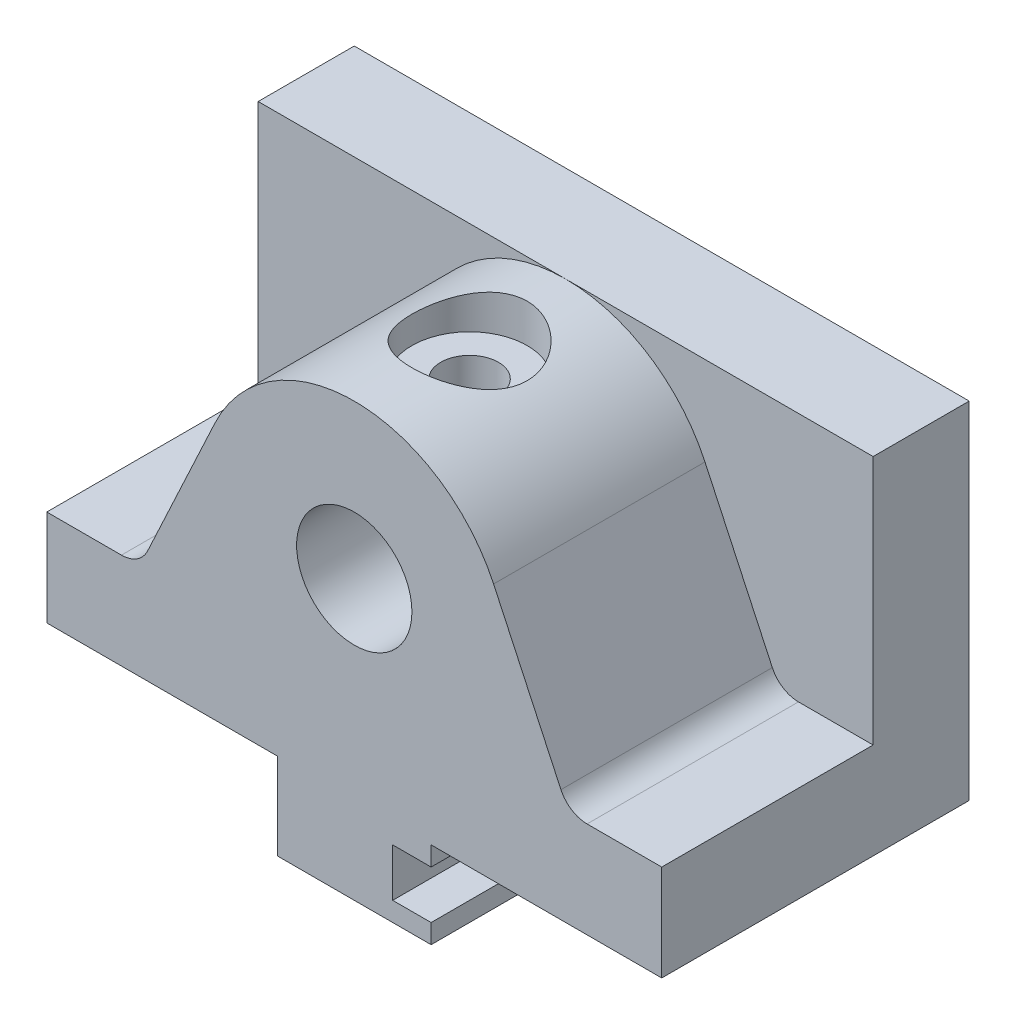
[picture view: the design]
ISO-10303-21;
HEADER;
FILE_DESCRIPTION(('STEP AP214'),'2;1');
FILE_NAME('part.step','',(''),(''),'','','');
FILE_SCHEMA(('AUTOMOTIVE_DESIGN { 1 0 10303 214 1 1 1 1 }'));
ENDSEC;
DATA;
#1=APPLICATION_CONTEXT('core data for automotive mechanical design processes');
#2=APPLICATION_PROTOCOL_DEFINITION('international standard','automotive_design',2000,#1);
#3=PRODUCT_CONTEXT('',#1,'mechanical');
#4=PRODUCT('Part','Part','',(#3));
#5=PRODUCT_RELATED_PRODUCT_CATEGORY('part','',(#4));
#6=PRODUCT_DEFINITION_FORMATION('','',#4);
#7=PRODUCT_DEFINITION_CONTEXT('part definition',#1,'design');
#8=PRODUCT_DEFINITION('design','',#6,#7);
#9=PRODUCT_DEFINITION_SHAPE('','',#8);
#10=(LENGTH_UNIT() NAMED_UNIT(*) SI_UNIT(.MILLI.,.METRE.));
#11=(NAMED_UNIT(*) PLANE_ANGLE_UNIT() SI_UNIT($,.RADIAN.));
#12=(NAMED_UNIT(*) SI_UNIT($,.STERADIAN.) SOLID_ANGLE_UNIT());
#13=UNCERTAINTY_MEASURE_WITH_UNIT(LENGTH_MEASURE(1.E-05),#10,'distance_accuracy_value','');
#14=(GEOMETRIC_REPRESENTATION_CONTEXT(3) GLOBAL_UNCERTAINTY_ASSIGNED_CONTEXT((#13)) GLOBAL_UNIT_ASSIGNED_CONTEXT((#10,
#11,#12)) REPRESENTATION_CONTEXT('',''));
#15=CARTESIAN_POINT('',(0.,0.,0.));
#16=DIRECTION('',(0.,0.,1.));
#17=DIRECTION('',(1.,0.,0.));
#18=AXIS2_PLACEMENT_3D('',#15,#16,#17);
#19=CARTESIAN_POINT('',(7.99999999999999,-9.,22.));
#20=DIRECTION('',(-1.,0.,0.));
#21=DIRECTION('',(0.,-1.,0.));
#22=AXIS2_PLACEMENT_3D('',#19,#20,#21);
#23=PLANE('',#22);
#24=DIRECTION('',(0.,1.,0.));
#25=VECTOR('',#24,1.);
#26=CARTESIAN_POINT('',(7.99999999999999,-9.,22.));
#27=LINE('',#26,#25);
#28=CARTESIAN_POINT('',(7.99999999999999,-2.,22.));
#29=VERTEX_POINT('',#28);
#30=CARTESIAN_POINT('',(8.,0.,22.));
#31=VERTEX_POINT('',#30);
#32=EDGE_CURVE('E333',#29,#31,#27,.T.);
#33=ORIENTED_EDGE('',*,*,#32,.F.);
#34=DIRECTION('',(0.,0.,1.));
#35=VECTOR('',#34,1.);
#36=CARTESIAN_POINT('',(7.99999999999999,-2.,-10.));
#37=LINE('',#36,#35);
#38=CARTESIAN_POINT('',(7.99999999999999,-2.,-10.));
#39=VERTEX_POINT('',#38);
#40=EDGE_CURVE('E218',#39,#29,#37,.T.);
#41=ORIENTED_EDGE('',*,*,#40,.F.);
#42=DIRECTION('',(0.,-1.,0.));
#43=VECTOR('',#42,1.);
#44=CARTESIAN_POINT('',(7.99999999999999,-9.,-10.));
#45=LINE('',#44,#43);
#46=CARTESIAN_POINT('',(8.,0.,-10.));
#47=VERTEX_POINT('',#46);
#48=EDGE_CURVE('E292',#47,#39,#45,.T.);
#49=ORIENTED_EDGE('',*,*,#48,.F.);
#50=DIRECTION('',(0.,0.,-1.));
#51=VECTOR('',#50,1.);
#52=CARTESIAN_POINT('',(8.,0.,22.));
#53=LINE('',#52,#51);
#54=EDGE_CURVE('E440',#31,#47,#53,.T.);
#55=ORIENTED_EDGE('',*,*,#54,.F.);
#56=EDGE_LOOP('',(#33,#41,#49,#55));
#57=FACE_BOUND('',#56,.T.);
#58=ADVANCED_FACE('F36',(#57),#23,.F.);
#59=CARTESIAN_POINT('',(-8.,0.,22.));
#60=DIRECTION('',(1.,0.,0.));
#61=DIRECTION('',(0.,1.,0.));
#62=AXIS2_PLACEMENT_3D('',#59,#60,#61);
#63=PLANE('',#62);
#64=DIRECTION('',(0.,0.,-1.));
#65=VECTOR('',#64,1.);
#66=CARTESIAN_POINT('',(-8.,0.,22.));
#67=LINE('',#66,#65);
#68=CARTESIAN_POINT('',(-8.,0.,22.));
#69=VERTEX_POINT('',#68);
#70=CARTESIAN_POINT('',(-8.,0.,-10.));
#71=VERTEX_POINT('',#70);
#72=EDGE_CURVE('E355',#69,#71,#67,.T.);
#73=ORIENTED_EDGE('',*,*,#72,.T.);
#74=DIRECTION('',(0.,1.,0.));
#75=VECTOR('',#74,1.);
#76=CARTESIAN_POINT('',(-8.,0.,-10.));
#77=LINE('',#76,#75);
#78=CARTESIAN_POINT('',(-8.00000000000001,-9.,-10.));
#79=VERTEX_POINT('',#78);
#80=EDGE_CURVE('E302',#79,#71,#77,.T.);
#81=ORIENTED_EDGE('',*,*,#80,.F.);
#82=DIRECTION('',(0.,0.,-1.));
#83=VECTOR('',#82,1.);
#84=CARTESIAN_POINT('',(-8.00000000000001,-9.,22.));
#85=LINE('',#84,#83);
#86=CARTESIAN_POINT('',(-8.00000000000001,-9.,22.));
#87=VERTEX_POINT('',#86);
#88=EDGE_CURVE('E378',#87,#79,#85,.T.);
#89=ORIENTED_EDGE('',*,*,#88,.F.);
#90=DIRECTION('',(0.,-1.,0.));
#91=VECTOR('',#90,1.);
#92=CARTESIAN_POINT('',(-8.,0.,22.));
#93=LINE('',#92,#91);
#94=EDGE_CURVE('E327',#69,#87,#93,.T.);
#95=ORIENTED_EDGE('',*,*,#94,.F.);
#96=EDGE_LOOP('',(#73,#81,#89,#95));
#97=FACE_BOUND('',#96,.T.);
#98=ADVANCED_FACE('F261',(#97),#63,.F.);
#99=CARTESIAN_POINT('',(-8.00000000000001,-9.,22.));
#100=DIRECTION('',(0.,1.,0.));
#101=DIRECTION('',(0.,0.,1.));
#102=AXIS2_PLACEMENT_3D('',#99,#100,#101);
#103=PLANE('',#102);
#104=CARTESIAN_POINT('',(0.,-9.,14.));
#105=DIRECTION('',(0.,-1.,0.));
#106=DIRECTION('',(0.,0.,-1.));
#107=AXIS2_PLACEMENT_3D('',#104,#105,#106);
#108=CIRCLE('',#107,3.);
#109=CARTESIAN_POINT('',(0.,-9.,11.));
#110=VERTEX_POINT('',#109);
#111=EDGE_CURVE('E233',#110,#110,#108,.T.);
#112=ORIENTED_EDGE('',*,*,#111,.F.);
#113=EDGE_LOOP('',(#112));
#114=FACE_BOUND('',#113,.T.);
#115=CARTESIAN_POINT('',(0.,-9.,-2.));
#116=DIRECTION('',(0.,-1.,0.));
#117=DIRECTION('',(0.,0.,-1.));
#118=AXIS2_PLACEMENT_3D('',#115,#116,#117);
#119=CIRCLE('',#118,3.);
#120=CARTESIAN_POINT('',(0.,-9.,-5.));
#121=VERTEX_POINT('',#120);
#122=EDGE_CURVE('E540',#121,#121,#119,.T.);
#123=ORIENTED_EDGE('',*,*,#122,.F.);
#124=EDGE_LOOP('',(#123));
#125=FACE_BOUND('',#124,.T.);
#126=ORIENTED_EDGE('',*,*,#88,.T.);
#127=DIRECTION('',(-1.,0.,0.));
#128=VECTOR('',#127,1.);
#129=CARTESIAN_POINT('',(-8.00000000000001,-9.,-10.));
#130=LINE('',#129,#128);
#131=CARTESIAN_POINT('',(7.99999999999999,-9.,-10.));
#132=VERTEX_POINT('',#131);
#133=EDGE_CURVE('E295',#132,#79,#130,.T.);
#134=ORIENTED_EDGE('',*,*,#133,.F.);
#135=DIRECTION('',(0.,0.,-1.));
#136=VECTOR('',#135,1.);
#137=CARTESIAN_POINT('',(7.99999999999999,-9.,22.));
#138=LINE('',#137,#136);
#139=CARTESIAN_POINT('',(7.99999999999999,-9.,22.));
#140=VERTEX_POINT('',#139);
#141=EDGE_CURVE('E289',#140,#132,#138,.T.);
#142=ORIENTED_EDGE('',*,*,#141,.F.);
#143=DIRECTION('',(1.,0.,0.));
#144=VECTOR('',#143,1.);
#145=CARTESIAN_POINT('',(-8.00000000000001,-9.,22.));
#146=LINE('',#145,#144);
#147=EDGE_CURVE('E330',#87,#140,#146,.T.);
#148=ORIENTED_EDGE('',*,*,#147,.F.);
#149=EDGE_LOOP('',(#126,#134,#142,#148));
#150=FACE_BOUND('',#149,.T.);
#151=ADVANCED_FACE('F268',(#114,#125,#150),#103,.F.);
#152=CARTESIAN_POINT('',(7.99999999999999,-7.,-10.));
#153=VERTEX_POINT('',#152);
#154=EDGE_CURVE('E285',#153,#132,#45,.T.);
#155=ORIENTED_EDGE('',*,*,#154,.F.);
#156=DIRECTION('',(0.,0.,1.));
#157=VECTOR('',#156,1.);
#158=CARTESIAN_POINT('',(7.99999999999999,-7.,-10.));
#159=LINE('',#158,#157);
#160=CARTESIAN_POINT('',(7.99999999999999,-7.,22.));
#161=VERTEX_POINT('',#160);
#162=EDGE_CURVE('E55',#153,#161,#159,.T.);
#163=ORIENTED_EDGE('',*,*,#162,.T.);
#164=EDGE_CURVE('E334',#140,#161,#27,.T.);
#165=ORIENTED_EDGE('',*,*,#164,.F.);
#166=ORIENTED_EDGE('',*,*,#141,.T.);
#167=EDGE_LOOP('',(#155,#163,#165,#166));
#168=FACE_BOUND('',#167,.T.);
#169=ADVANCED_FACE('F264',(#168),#23,.F.);
#170=CARTESIAN_POINT('',(8.,0.,22.));
#171=DIRECTION('',(0.,1.,0.));
#172=DIRECTION('',(0.,0.,1.));
#173=AXIS2_PLACEMENT_3D('',#170,#171,#172);
#174=PLANE('',#173);
#175=ORIENTED_EDGE('',*,*,#54,.T.);
#176=DIRECTION('',(-1.,0.,0.));
#177=VECTOR('',#176,1.);
#178=CARTESIAN_POINT('',(8.,0.,-10.));
#179=LINE('',#178,#177);
#180=CARTESIAN_POINT('',(32.,0.,-10.));
#181=VERTEX_POINT('',#180);
#182=EDGE_CURVE('E293',#181,#47,#179,.T.);
#183=ORIENTED_EDGE('',*,*,#182,.F.);
#184=DIRECTION('',(0.,0.,-1.));
#185=VECTOR('',#184,1.);
#186=CARTESIAN_POINT('',(32.,0.,22.));
#187=LINE('',#186,#185);
#188=CARTESIAN_POINT('',(32.,0.,22.));
#189=VERTEX_POINT('',#188);
#190=EDGE_CURVE('E422',#189,#181,#187,.T.);
#191=ORIENTED_EDGE('',*,*,#190,.F.);
#192=DIRECTION('',(1.,0.,0.));
#193=VECTOR('',#192,1.);
#194=CARTESIAN_POINT('',(8.,0.,22.));
#195=LINE('',#194,#193);
#196=EDGE_CURVE('E336',#31,#189,#195,.T.);
#197=ORIENTED_EDGE('',*,*,#196,.F.);
#198=EDGE_LOOP('',(#175,#183,#191,#197));
#199=FACE_BOUND('',#198,.T.);
#200=ADVANCED_FACE('F275',(#199),#174,.F.);
#201=CARTESIAN_POINT('',(32.,0.,22.));
#202=DIRECTION('',(-1.,0.,0.));
#203=DIRECTION('',(0.,0.,1.));
#204=AXIS2_PLACEMENT_3D('',#201,#202,#203);
#205=PLANE('',#204);
#206=ORIENTED_EDGE('',*,*,#190,.T.);
#207=DIRECTION('',(0.,-1.,0.));
#208=VECTOR('',#207,1.);
#209=CARTESIAN_POINT('',(32.,36.,-10.));
#210=LINE('',#209,#208);
#211=CARTESIAN_POINT('',(32.,36.,-10.));
#212=VERTEX_POINT('',#211);
#213=EDGE_CURVE('E312',#212,#181,#210,.T.);
#214=ORIENTED_EDGE('',*,*,#213,.F.);
#215=DIRECTION('',(0.,0.,1.));
#216=VECTOR('',#215,1.);
#217=CARTESIAN_POINT('',(32.,36.,-10.));
#218=LINE('',#217,#216);
#219=CARTESIAN_POINT('',(32.,36.,0.));
#220=VERTEX_POINT('',#219);
#221=EDGE_CURVE('E315',#212,#220,#218,.T.);
#222=ORIENTED_EDGE('',*,*,#221,.T.);
#223=DIRECTION('',(0.,-1.,0.));
#224=VECTOR('',#223,1.);
#225=CARTESIAN_POINT('',(32.,0.,0.));
#226=LINE('',#225,#224);
#227=CARTESIAN_POINT('',(32.,10.,0.));
#228=VERTEX_POINT('',#227);
#229=EDGE_CURVE('E297',#220,#228,#226,.T.);
#230=ORIENTED_EDGE('',*,*,#229,.T.);
#231=DIRECTION('',(0.,0.,-1.));
#232=VECTOR('',#231,1.);
#233=CARTESIAN_POINT('',(32.,10.,22.));
#234=LINE('',#233,#232);
#235=CARTESIAN_POINT('',(32.,10.,22.));
#236=VERTEX_POINT('',#235);
#237=EDGE_CURVE('E412',#236,#228,#234,.T.);
#238=ORIENTED_EDGE('',*,*,#237,.F.);
#239=DIRECTION('',(0.,1.,0.));
#240=VECTOR('',#239,1.);
#241=CARTESIAN_POINT('',(32.,0.,22.));
#242=LINE('',#241,#240);
#243=EDGE_CURVE('E338',#189,#236,#242,.T.);
#244=ORIENTED_EDGE('',*,*,#243,.F.);
#245=EDGE_LOOP('',(#206,#214,#222,#230,#238,#244));
#246=FACE_BOUND('',#245,.T.);
#247=ADVANCED_FACE('F281',(#246),#205,.F.);
#248=CARTESIAN_POINT('',(32.,10.,22.));
#249=DIRECTION('',(0.,-1.,0.));
#250=DIRECTION('',(1.,0.,0.));
#251=AXIS2_PLACEMENT_3D('',#248,#249,#250);
#252=PLANE('',#251);
#253=DIRECTION('',(-1.,0.,0.));
#254=VECTOR('',#253,1.);
#255=CARTESIAN_POINT('',(32.,10.,0.));
#256=LINE('',#255,#254);
#257=CARTESIAN_POINT('',(24.2283340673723,9.99999999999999,0.));
#258=VERTEX_POINT('',#257);
#259=EDGE_CURVE('E359',#228,#258,#256,.T.);
#260=ORIENTED_EDGE('',*,*,#259,.T.);
#261=DIRECTION('',(0.,0.,-1.));
#262=VECTOR('',#261,1.);
#263=CARTESIAN_POINT('',(24.2283340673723,9.99999999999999,22.));
#264=LINE('',#263,#262);
#265=CARTESIAN_POINT('',(24.2283340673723,9.99999999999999,22.));
#266=VERTEX_POINT('',#265);
#267=EDGE_CURVE('E63',#258,#266,#264,.F.);
#268=ORIENTED_EDGE('',*,*,#267,.T.);
#269=DIRECTION('',(-1.,0.,0.));
#270=VECTOR('',#269,1.);
#271=CARTESIAN_POINT('',(32.,10.,22.));
#272=LINE('',#271,#270);
#273=EDGE_CURVE('E340',#236,#266,#272,.T.);
#274=ORIENTED_EDGE('',*,*,#273,.F.);
#275=ORIENTED_EDGE('',*,*,#237,.T.);
#276=EDGE_LOOP('',(#260,#268,#274,#275));
#277=FACE_BOUND('',#276,.T.);
#278=ADVANCED_FACE('F410',(#277),#252,.F.);
#279=CARTESIAN_POINT('',(22.3171232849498,9.99999999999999,22.));
#280=DIRECTION('',(-0.906307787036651,-0.422618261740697,0.));
#281=DIRECTION('',(0.422618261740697,-0.906307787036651,0.));
#282=AXIS2_PLACEMENT_3D('',#279,#280,#281);
#283=PLANE('',#282);
#284=DIRECTION('',(-0.422618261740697,0.906307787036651,0.));
#285=VECTOR('',#284,1.);
#286=CARTESIAN_POINT('',(22.3171232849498,9.99999999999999,22.));
#287=LINE('',#286,#285);
#288=CARTESIAN_POINT('',(21.5094107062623,11.7321452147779,22.));
#289=VERTEX_POINT('',#288);
#290=CARTESIAN_POINT('',(14.5009245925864,26.7618921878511,22.));
#291=VERTEX_POINT('',#290);
#292=EDGE_CURVE('E342',#289,#291,#287,.T.);
#293=ORIENTED_EDGE('',*,*,#292,.F.);
#294=DIRECTION('',(0.,0.,-1.));
#295=VECTOR('',#294,1.);
#296=CARTESIAN_POINT('',(21.5094107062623,11.7321452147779,0.));
#297=LINE('',#296,#295);
#298=CARTESIAN_POINT('',(21.5094107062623,11.7321452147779,0.));
#299=VERTEX_POINT('',#298);
#300=EDGE_CURVE('E382',#289,#299,#297,.T.);
#301=ORIENTED_EDGE('',*,*,#300,.T.);
#302=DIRECTION('',(-0.422618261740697,0.906307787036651,0.));
#303=VECTOR('',#302,1.);
#304=CARTESIAN_POINT('',(22.3171232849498,9.99999999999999,0.));
#305=LINE('',#304,#303);
#306=CARTESIAN_POINT('',(14.5009245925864,26.7618921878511,0.));
#307=VERTEX_POINT('',#306);
#308=EDGE_CURVE('E356',#299,#307,#305,.T.);
#309=ORIENTED_EDGE('',*,*,#308,.T.);
#310=DIRECTION('',(0.,0.,-1.));
#311=VECTOR('',#310,1.);
#312=CARTESIAN_POINT('',(14.5009245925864,26.7618921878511,22.));
#313=LINE('',#312,#311);
#314=EDGE_CURVE('E402',#291,#307,#313,.T.);
#315=ORIENTED_EDGE('',*,*,#314,.F.);
#316=EDGE_LOOP('',(#293,#301,#309,#315));
#317=FACE_BOUND('',#316,.T.);
#318=ADVANCED_FACE('F399',(#317),#283,.F.);
#319=CARTESIAN_POINT('',(0.,20.,22.));
#320=DIRECTION('',(0.,0.,-1.));
#321=DIRECTION('',(-1.,0.,0.));
#322=AXIS2_PLACEMENT_3D('',#319,#320,#321);
#323=CYLINDRICAL_SURFACE('',#322,16.);
#324=CARTESIAN_POINT('',(0.,36.,16.));
#325=CARTESIAN_POINT('',(-0.162427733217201,36.0000005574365,16.0000007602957));
#326=CARTESIAN_POINT('',(-0.324844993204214,35.997521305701,15.9933993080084));
#327=CARTESIAN_POINT('',(-0.648520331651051,35.9876715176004,15.9670588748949));
#328=CARTESIAN_POINT('',(-0.809777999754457,35.9802993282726,15.9473154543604));
#329=CARTESIAN_POINT('',(-1.12979634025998,35.9608661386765,15.8948993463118));
#330=CARTESIAN_POINT('',(-1.28855831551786,35.9488076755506,15.862233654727));
#331=CARTESIAN_POINT('',(-1.60261141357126,35.920317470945,15.7842738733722));
#332=CARTESIAN_POINT('',(-1.75790116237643,35.9038840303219,15.7389748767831));
#333=CARTESIAN_POINT('',(-2.06353693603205,35.8671186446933,15.6362882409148));
#334=CARTESIAN_POINT('',(-2.2138937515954,35.8467959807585,15.5789293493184));
#335=CARTESIAN_POINT('',(-2.50915130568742,35.8027355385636,15.4525186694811));
#336=CARTESIAN_POINT('',(-2.6540499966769,35.7789964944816,15.3834625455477));
#337=CARTESIAN_POINT('',(-2.93745114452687,35.7287028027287,15.2342168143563));
#338=CARTESIAN_POINT('',(-3.07595454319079,35.7021485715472,15.1540288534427));
#339=CARTESIAN_POINT('',(-3.3458591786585,35.6468595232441,14.9830470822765));
#340=CARTESIAN_POINT('',(-3.47725782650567,35.618123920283,14.8922494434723));
#341=CARTESIAN_POINT('',(-3.73705610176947,35.5580480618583,14.6970003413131));
#342=CARTESIAN_POINT('',(-3.86515055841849,35.5266502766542,14.5921603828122));
#343=CARTESIAN_POINT('',(-4.11214204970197,35.4630706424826,14.372369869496));
#344=CARTESIAN_POINT('',(-4.23103881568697,35.4308887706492,14.2574190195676));
#345=CARTESIAN_POINT('',(-4.45900396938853,35.3665649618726,14.0180360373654));
#346=CARTESIAN_POINT('',(-4.56806779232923,35.334423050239,13.8935995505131));
#347=CARTESIAN_POINT('',(-4.7756151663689,35.2710599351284,13.6360477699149));
#348=CARTESIAN_POINT('',(-4.87410227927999,35.2398384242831,13.5029354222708));
#349=CARTESIAN_POINT('',(-5.06349317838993,35.1779887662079,13.2234482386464));
#350=CARTESIAN_POINT('',(-5.15395768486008,35.1474300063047,13.0767598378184));
#351=CARTESIAN_POINT('',(-5.32210766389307,35.0891712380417,12.7757656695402));
#352=CARTESIAN_POINT('',(-5.39979826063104,35.0614700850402,12.6214629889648));
#353=CARTESIAN_POINT('',(-5.54178841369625,35.0098065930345,12.3061815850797));
#354=CARTESIAN_POINT('',(-5.60608640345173,34.9858446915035,12.1452020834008));
#355=CARTESIAN_POINT('',(-5.72063465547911,34.9424928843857,11.81780057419));
#356=CARTESIAN_POINT('',(-5.77089169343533,34.9231007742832,11.6513812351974));
#357=CARTESIAN_POINT('',(-5.85511762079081,34.8902504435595,11.3211525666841));
#358=CARTESIAN_POINT('',(-5.88966490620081,34.8765832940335,11.1575115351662));
#359=CARTESIAN_POINT('',(-5.94499608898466,34.8545586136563,10.8276330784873));
#360=CARTESIAN_POINT('',(-5.96578600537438,34.8461987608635,10.6613968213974));
#361=CARTESIAN_POINT('',(-5.99338932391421,34.8350769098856,10.3276054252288));
#362=CARTESIAN_POINT('',(-6.00020481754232,34.8323140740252,10.1600504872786));
#363=CARTESIAN_POINT('',(-5.99978582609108,34.8324836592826,9.82496442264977));
#364=CARTESIAN_POINT('',(-5.99255188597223,34.8354158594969,9.65743329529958));
#365=CARTESIAN_POINT('',(-5.9649764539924,34.8465233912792,9.33379681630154));
#366=CARTESIAN_POINT('',(-5.94544909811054,34.8543729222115,9.17761005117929));
#367=CARTESIAN_POINT('',(-5.89424692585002,34.8747642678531,8.86749914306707));
#368=CARTESIAN_POINT('',(-5.86256807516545,34.887307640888,8.713575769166));
#369=CARTESIAN_POINT('',(-5.78737202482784,34.9167004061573,8.40911721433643));
#370=CARTESIAN_POINT('',(-5.74385788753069,34.9335486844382,8.25858116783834));
#371=CARTESIAN_POINT('',(-5.64535023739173,34.9710653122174,7.96174446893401));
#372=CARTESIAN_POINT('',(-5.59035233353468,34.9917351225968,7.8154454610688));
#373=CARTESIAN_POINT('',(-5.46820476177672,35.0367233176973,7.52533536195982));
#374=CARTESIAN_POINT('',(-5.40084887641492,35.0611021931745,7.3816205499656));
#375=CARTESIAN_POINT('',(-5.25517504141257,35.112547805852,7.10030421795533));
#376=CARTESIAN_POINT('',(-5.17685336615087,35.1396154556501,6.96270479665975));
#377=CARTESIAN_POINT('',(-5.00978390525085,35.1957174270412,6.69439199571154));
#378=CARTESIAN_POINT('',(-4.92103495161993,35.2247519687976,6.56367938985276));
#379=CARTESIAN_POINT('',(-4.73365945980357,35.2840480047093,6.30982948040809));
#380=CARTESIAN_POINT('',(-4.63503247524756,35.3143095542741,6.18669251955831));
#381=CARTESIAN_POINT('',(-4.42148606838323,35.3773753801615,5.94059609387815));
#382=CARTESIAN_POINT('',(-4.30591643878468,35.4102134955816,5.81820873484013));
#383=CARTESIAN_POINT('',(-4.06489568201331,35.4755357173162,5.58356444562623));
#384=CARTESIAN_POINT('',(-3.93944756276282,35.5080199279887,5.47130445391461));
#385=CARTESIAN_POINT('',(-3.67930542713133,35.5717902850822,5.25752502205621));
#386=CARTESIAN_POINT('',(-3.54460652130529,35.6030757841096,5.15601133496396));
#387=CARTESIAN_POINT('',(-3.26687700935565,35.6635788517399,4.96453057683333));
#388=CARTESIAN_POINT('',(-3.1238497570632,35.6927972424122,4.87455890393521));
#389=CARTESIAN_POINT('',(-2.8279450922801,35.7488334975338,4.7054533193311));
#390=CARTESIAN_POINT('',(-2.67494692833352,35.7756056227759,4.62651523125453));
#391=CARTESIAN_POINT('',(-2.3622882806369,35.8254428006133,4.48191640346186));
#392=CARTESIAN_POINT('',(-2.20263047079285,35.8485093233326,4.4162503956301));
#393=CARTESIAN_POINT('',(-1.87775996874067,35.8902747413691,4.29878554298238));
#394=CARTESIAN_POINT('',(-1.71254812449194,35.9089742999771,4.24698459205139));
#395=CARTESIAN_POINT('',(-1.37781252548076,35.941452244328,4.15777194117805));
#396=CARTESIAN_POINT('',(-1.20828902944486,35.9552309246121,4.12035938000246));
#397=CARTESIAN_POINT('',(-0.875397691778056,35.9768584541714,4.06192787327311));
#398=CARTESIAN_POINT('',(-0.71218192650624,35.9849836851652,4.04014291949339));
#399=CARTESIAN_POINT('',(-0.384342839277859,35.9962238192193,4.01006070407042));
#400=CARTESIAN_POINT('',(-0.219719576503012,35.9993389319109,4.00176287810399));
#401=CARTESIAN_POINT('',(0.10963649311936,36.0004717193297,3.99874206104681));
#402=CARTESIAN_POINT('',(0.274369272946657,35.9984903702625,4.0040164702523));
#403=CARTESIAN_POINT('',(0.602703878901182,35.9894877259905,4.02807883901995));
#404=CARTESIAN_POINT('',(0.766305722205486,35.9824665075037,4.04686659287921));
#405=CARTESIAN_POINT('',(1.08484961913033,35.9639458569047,4.09677376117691));
#406=CARTESIAN_POINT('',(1.23988188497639,35.9526301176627,4.1273881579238));
#407=CARTESIAN_POINT('',(1.54675761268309,35.9258052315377,4.20065226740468));
#408=CARTESIAN_POINT('',(1.69860000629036,35.9102947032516,4.24330594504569));
#409=CARTESIAN_POINT('',(1.99802063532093,35.8754724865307,4.3402587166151));
#410=CARTESIAN_POINT('',(2.14560001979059,35.85616183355,4.39455463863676));
#411=CARTESIAN_POINT('',(2.43569439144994,35.8141987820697,4.51437951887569));
#412=CARTESIAN_POINT('',(2.5782074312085,35.791545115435,4.57991274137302));
#413=CARTESIAN_POINT('',(2.8613459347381,35.7427421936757,4.72376640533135));
#414=CARTESIAN_POINT('',(3.00179672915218,35.7165106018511,4.80240263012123));
#415=CARTESIAN_POINT('',(3.27565209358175,35.6617244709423,4.97049434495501));
#416=CARTESIAN_POINT('',(3.40905422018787,35.6331691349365,5.05995355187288));
#417=CARTESIAN_POINT('',(3.66805220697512,35.574435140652,5.24909372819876));
#418=CARTESIAN_POINT('',(3.79364691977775,35.5442562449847,5.34877619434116));
#419=CARTESIAN_POINT('',(4.03634135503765,35.4830105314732,5.55774902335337));
#420=CARTESIAN_POINT('',(4.1534407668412,35.4519436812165,5.66703973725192));
#421=CARTESIAN_POINT('',(4.3850769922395,35.3878643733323,5.9012462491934));
#422=CARTESIAN_POINT('',(4.49906697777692,35.3548440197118,6.02670141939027));
#423=CARTESIAN_POINT('',(4.71608180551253,35.2895850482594,6.28687984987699));
#424=CARTESIAN_POINT('',(4.81911014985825,35.2573461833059,6.42160012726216));
#425=CARTESIAN_POINT('',(5.01360921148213,35.194544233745,6.69961873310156));
#426=CARTESIAN_POINT('',(5.10507411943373,35.163981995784,6.84292132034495));
#427=CARTESIAN_POINT('',(5.27567954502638,35.1054737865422,7.13711577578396));
#428=CARTESIAN_POINT('',(5.35482524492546,35.0775267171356,7.2880044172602));
#429=CARTESIAN_POINT('',(5.50053123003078,35.0249854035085,7.59718997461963));
#430=CARTESIAN_POINT('',(5.5670312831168,35.0004073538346,7.75551807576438));
#431=CARTESIAN_POINT('',(5.68634828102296,34.9555845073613,8.07777478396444));
#432=CARTESIAN_POINT('',(5.73917096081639,34.9353378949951,8.241701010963));
#433=CARTESIAN_POINT('',(5.8306145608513,34.89987725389,8.57395243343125));
#434=CARTESIAN_POINT('',(5.86923979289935,34.884661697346,8.74227627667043));
#435=CARTESIAN_POINT('',(5.93187603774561,34.8598111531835,9.08202494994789));
#436=CARTESIAN_POINT('',(5.95588806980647,34.8501757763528,9.25344956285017));
#437=CARTESIAN_POINT('',(5.98795090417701,34.8372746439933,9.58688079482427));
#438=CARTESIAN_POINT('',(5.99692832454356,34.8336393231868,9.74878464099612));
#439=CARTESIAN_POINT('',(6.00174553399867,34.8316910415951,10.0728179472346));
#440=CARTESIAN_POINT('',(5.99758576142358,34.8333779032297,10.2349473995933));
#441=CARTESIAN_POINT('',(5.97617513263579,34.8420167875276,10.5581793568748));
#442=CARTESIAN_POINT('',(5.9589255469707,34.8489682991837,10.7192819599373));
#443=CARTESIAN_POINT('',(5.91152013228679,34.8679043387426,11.0392740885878));
#444=CARTESIAN_POINT('',(5.88136431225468,34.8798888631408,11.1981636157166));
#445=CARTESIAN_POINT('',(5.80957518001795,34.9080606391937,11.5077481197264));
#446=CARTESIAN_POINT('',(5.76832374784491,34.9241071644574,11.65854478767));
#447=CARTESIAN_POINT('',(5.67433519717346,34.9600952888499,11.9560860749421));
#448=CARTESIAN_POINT('',(5.62159429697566,34.9800381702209,12.1028293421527));
#449=CARTESIAN_POINT('',(5.50506367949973,35.0232530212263,12.3913315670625));
#450=CARTESIAN_POINT('',(5.44127561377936,35.0465244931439,12.5330912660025));
#451=CARTESIAN_POINT('',(5.30311395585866,35.0957729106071,12.8108859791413));
#452=CARTESIAN_POINT('',(5.22873653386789,35.1217508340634,12.9469188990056));
#453=CARTESIAN_POINT('',(4.98217098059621,35.2055628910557,13.359141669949));
#454=CARTESIAN_POINT('',(4.79257489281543,35.2669336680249,13.6244522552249));
#455=CARTESIAN_POINT('',(4.37331782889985,35.3922641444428,14.1206371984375));
#456=CARTESIAN_POINT('',(4.14364411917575,35.4562246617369,14.3515005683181));
#457=CARTESIAN_POINT('',(3.76647526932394,35.5509413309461,14.6736561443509));
#458=CARTESIAN_POINT('',(3.63140882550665,35.5831105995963,14.7793645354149));
#459=CARTESIAN_POINT('',(3.35244180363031,35.6454953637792,14.979007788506));
#460=CARTESIAN_POINT('',(3.2085445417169,35.6757115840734,15.0729470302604));
#461=CARTESIAN_POINT('',(2.9127270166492,35.7333640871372,15.2483917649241));
#462=CARTESIAN_POINT('',(2.76080251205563,35.7607988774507,15.3298905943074));
#463=CARTESIAN_POINT('',(2.45006904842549,35.8120821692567,15.4796800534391));
#464=CARTESIAN_POINT('',(2.29126304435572,35.8359321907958,15.5479762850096));
#465=CARTESIAN_POINT('',(1.96075860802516,35.8803154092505,15.6734482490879));
#466=CARTESIAN_POINT('',(1.78880001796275,35.9006582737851,15.7300080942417));
#467=CARTESIAN_POINT('',(1.43995213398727,35.9360368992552,15.8274639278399));
#468=CARTESIAN_POINT('',(1.26306259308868,35.9510723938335,15.8683591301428));
#469=CARTESIAN_POINT('',(0.905989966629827,35.9753306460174,15.9339800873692));
#470=CARTESIAN_POINT('',(0.725808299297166,35.9845558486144,15.9587126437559));
#471=CARTESIAN_POINT('',(0.363746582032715,35.9968898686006,15.9917212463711));
#472=CARTESIAN_POINT('',(0.181866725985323,35.9999993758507,15.9999991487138));
#473=CARTESIAN_POINT('',(0.,36.,16.));
#474=B_SPLINE_CURVE_WITH_KNOTS('',3,(#324,#325,#326,#327,#328,#329,#330,#331,#332,#333,#334,
#335,#336,#337,#338,#339,#340,#341,#342,#343,#344,#345,#346,#347,#348,#349,#350,#351,#352,#353,
#354,#355,#356,#357,#358,#359,#360,#361,#362,#363,#364,#365,#366,#367,#368,#369,#370,#371,#372,
#373,#374,#375,#376,#377,#378,#379,#380,#381,#382,#383,#384,#385,#386,#387,#388,#389,#390,#391,
#392,#393,#394,#395,#396,#397,#398,#399,#400,#401,#402,#403,#404,#405,#406,#407,#408,#409,#410,
#411,#412,#413,#414,#415,#416,#417,#418,#419,#420,#421,#422,#423,#424,#425,#426,#427,#428,#429,
#430,#431,#432,#433,#434,#435,#436,#437,#438,#439,#440,#441,#442,#443,#444,#445,#446,#447,#448,
#449,#450,#451,#452,#453,#454,#455,#456,#457,#458,#459,#460,#461,#462,#463,#464,#465,#466,#467,
#468,#469,#470,#471,#472,#473),.UNSPECIFIED.,.T.,.F.,(4,2,2,2,2,2,2,2,2,2,2,2,2,2,2,2,2,2,2,2,2,
2,2,2,2,2,2,2,2,2,2,2,2,2,2,2,2,2,2,2,2,2,2,2,2,2,2,2,2,2,2,2,2,2,2,2,2,2,2,2,2,2,2,2,2,2,2,2,2,
2,2,2,2,2,4),(0.,0.48711292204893,0.974390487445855,1.46140460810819,1.94860815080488,
2.43466323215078,2.92089887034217,3.40706267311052,3.89340245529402,4.39827808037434,
4.90316844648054,5.40829200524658,5.91324492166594,6.43768308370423,6.96191035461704,
7.48619891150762,8.01023402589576,8.51299593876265,9.01553774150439,9.51800432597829,
10.0204514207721,10.4926927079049,10.9650909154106,11.4373670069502,11.9098240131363,
12.3910323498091,12.8724045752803,13.3538307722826,13.8352787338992,14.349198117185,
14.8629616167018,15.3769987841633,15.8908303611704,16.4128602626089,16.9346825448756,
17.4564255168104,17.9781372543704,18.4721042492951,18.9660505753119,19.4599022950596,
19.9537464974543,20.4284916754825,20.9033933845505,21.3781658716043,21.8531189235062,
22.3418491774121,22.830747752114,23.3197180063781,23.8087061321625,24.3261847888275,
24.8434976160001,25.3610693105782,25.8784226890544,26.3981817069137,26.9177224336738,
27.4371052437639,27.9564518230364,28.4424210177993,28.9283739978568,29.4142798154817,
29.9001852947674,30.3711334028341,30.8422367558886,31.3132697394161,31.7844735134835,
32.7753369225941,33.7665157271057,34.2894950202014,34.8122791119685,35.3353422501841,
35.8581829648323,36.4038564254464,36.9495572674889,37.4950283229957,38.0404378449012),.UNSPECIFIED.);
#475=CARTESIAN_POINT('',(0.,36.,16.));
#476=VERTEX_POINT('',#475);
#477=EDGE_CURVE('E11',#476,#476,#474,.T.);
#478=ORIENTED_EDGE('',*,*,#477,.T.);
#479=EDGE_LOOP('',(#478));
#480=FACE_BOUND('',#479,.T.);
#481=CARTESIAN_POINT('',(0.,20.,0.));
#482=DIRECTION('',(0.,0.,1.));
#483=DIRECTION('',(1.,0.,0.));
#484=AXIS2_PLACEMENT_3D('',#481,#482,#483);
#485=CIRCLE('',#484,16.);
#486=CARTESIAN_POINT('',(0.,36.,0.));
#487=VERTEX_POINT('',#486);
#488=EDGE_CURVE('E360',#307,#487,#485,.T.);
#489=ORIENTED_EDGE('',*,*,#488,.T.);
#490=CARTESIAN_POINT('',(-14.5009245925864,26.7618921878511,0.));
#491=VERTEX_POINT('',#490);
#492=EDGE_CURVE('E358',#487,#491,#485,.T.);
#493=ORIENTED_EDGE('',*,*,#492,.T.);
#494=DIRECTION('',(0.,0.,-1.));
#495=VECTOR('',#494,1.);
#496=CARTESIAN_POINT('',(-14.5009245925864,26.7618921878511,22.));
#497=LINE('',#496,#495);
#498=CARTESIAN_POINT('',(-14.5009245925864,26.7618921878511,22.));
#499=VERTEX_POINT('',#498);
#500=EDGE_CURVE('E426',#499,#491,#497,.T.);
#501=ORIENTED_EDGE('',*,*,#500,.F.);
#502=CARTESIAN_POINT('',(0.,20.,22.));
#503=DIRECTION('',(0.,0.,1.));
#504=DIRECTION('',(1.,0.,0.));
#505=AXIS2_PLACEMENT_3D('',#502,#503,#504);
#506=CIRCLE('',#505,16.);
#507=EDGE_CURVE('E344',#291,#499,#506,.T.);
#508=ORIENTED_EDGE('',*,*,#507,.F.);
#509=ORIENTED_EDGE('',*,*,#314,.T.);
#510=EDGE_LOOP('',(#489,#493,#501,#508,#509));
#511=FACE_BOUND('',#510,.T.);
#512=ADVANCED_FACE('F487',(#480,#511),#323,.T.);
#513=CARTESIAN_POINT('',(-14.5009245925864,26.7618921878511,22.));
#514=DIRECTION('',(0.906307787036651,-0.422618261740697,0.));
#515=DIRECTION('',(0.422618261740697,0.906307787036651,0.));
#516=AXIS2_PLACEMENT_3D('',#513,#514,#515);
#517=PLANE('',#516);
#518=DIRECTION('',(-0.422618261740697,-0.906307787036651,0.));
#519=VECTOR('',#518,1.);
#520=CARTESIAN_POINT('',(-14.5009245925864,26.7618921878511,0.));
#521=LINE('',#520,#519);
#522=CARTESIAN_POINT('',(-21.5094107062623,11.7321452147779,0.));
#523=VERTEX_POINT('',#522);
#524=EDGE_CURVE('E363',#491,#523,#521,.T.);
#525=ORIENTED_EDGE('',*,*,#524,.T.);
#526=DIRECTION('',(0.,0.,-1.));
#527=VECTOR('',#526,1.);
#528=CARTESIAN_POINT('',(-21.5094107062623,11.7321452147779,22.));
#529=LINE('',#528,#527);
#530=CARTESIAN_POINT('',(-21.5094107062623,11.7321452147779,22.));
#531=VERTEX_POINT('',#530);
#532=EDGE_CURVE('E380',#523,#531,#529,.F.);
#533=ORIENTED_EDGE('',*,*,#532,.T.);
#534=DIRECTION('',(-0.422618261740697,-0.906307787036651,0.));
#535=VECTOR('',#534,1.);
#536=CARTESIAN_POINT('',(-14.5009245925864,26.7618921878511,22.));
#537=LINE('',#536,#535);
#538=EDGE_CURVE('E346',#499,#531,#537,.T.);
#539=ORIENTED_EDGE('',*,*,#538,.F.);
#540=ORIENTED_EDGE('',*,*,#500,.T.);
#541=EDGE_LOOP('',(#525,#533,#539,#540));
#542=FACE_BOUND('',#541,.T.);
#543=ADVANCED_FACE('F491',(#542),#517,.F.);
#544=CARTESIAN_POINT('',(-22.3171232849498,9.99999999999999,22.));
#545=DIRECTION('',(0.,-1.,0.));
#546=DIRECTION('',(1.,0.,0.));
#547=AXIS2_PLACEMENT_3D('',#544,#545,#546);
#548=PLANE('',#547);
#549=DIRECTION('',(-1.,0.,0.));
#550=VECTOR('',#549,1.);
#551=CARTESIAN_POINT('',(-22.3171232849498,9.99999999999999,22.));
#552=LINE('',#551,#550);
#553=CARTESIAN_POINT('',(-24.2283340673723,9.99999999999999,22.));
#554=VERTEX_POINT('',#553);
#555=CARTESIAN_POINT('',(-32.,10.,22.));
#556=VERTEX_POINT('',#555);
#557=EDGE_CURVE('E349',#554,#556,#552,.T.);
#558=ORIENTED_EDGE('',*,*,#557,.F.);
#559=DIRECTION('',(0.,0.,-1.));
#560=VECTOR('',#559,1.);
#561=CARTESIAN_POINT('',(-24.2283340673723,9.99999999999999,0.));
#562=LINE('',#561,#560);
#563=CARTESIAN_POINT('',(-24.2283340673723,9.99999999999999,0.));
#564=VERTEX_POINT('',#563);
#565=EDGE_CURVE('E374',#554,#564,#562,.T.);
#566=ORIENTED_EDGE('',*,*,#565,.T.);
#567=DIRECTION('',(-1.,0.,0.));
#568=VECTOR('',#567,1.);
#569=CARTESIAN_POINT('',(-22.3171232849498,9.99999999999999,0.));
#570=LINE('',#569,#568);
#571=CARTESIAN_POINT('',(-32.,10.,0.));
#572=VERTEX_POINT('',#571);
#573=EDGE_CURVE('E331',#564,#572,#570,.T.);
#574=ORIENTED_EDGE('',*,*,#573,.T.);
#575=DIRECTION('',(0.,0.,-1.));
#576=VECTOR('',#575,1.);
#577=CARTESIAN_POINT('',(-32.,10.,22.));
#578=LINE('',#577,#576);
#579=EDGE_CURVE('E424',#556,#572,#578,.T.);
#580=ORIENTED_EDGE('',*,*,#579,.F.);
#581=EDGE_LOOP('',(#558,#566,#574,#580));
#582=FACE_BOUND('',#581,.T.);
#583=ADVANCED_FACE('F471',(#582),#548,.F.);
#584=CARTESIAN_POINT('',(-32.,10.,22.));
#585=DIRECTION('',(1.,0.,0.));
#586=DIRECTION('',(0.,0.,-1.));
#587=AXIS2_PLACEMENT_3D('',#584,#585,#586);
#588=PLANE('',#587);
#589=ORIENTED_EDGE('',*,*,#579,.T.);
#590=DIRECTION('',(0.,1.,0.));
#591=VECTOR('',#590,1.);
#592=CARTESIAN_POINT('',(-32.,36.,0.));
#593=LINE('',#592,#591);
#594=CARTESIAN_POINT('',(-32.,36.,0.));
#595=VERTEX_POINT('',#594);
#596=EDGE_CURVE('E321',#572,#595,#593,.T.);
#597=ORIENTED_EDGE('',*,*,#596,.T.);
#598=DIRECTION('',(0.,0.,1.));
#599=VECTOR('',#598,1.);
#600=CARTESIAN_POINT('',(-32.,36.,-10.));
#601=LINE('',#600,#599);
#602=CARTESIAN_POINT('',(-32.,36.,-10.));
#603=VERTEX_POINT('',#602);
#604=EDGE_CURVE('E413',#603,#595,#601,.T.);
#605=ORIENTED_EDGE('',*,*,#604,.F.);
#606=DIRECTION('',(0.,1.,0.));
#607=VECTOR('',#606,1.);
#608=CARTESIAN_POINT('',(-32.,10.,-10.));
#609=LINE('',#608,#607);
#610=CARTESIAN_POINT('',(-32.,0.,-10.));
#611=VERTEX_POINT('',#610);
#612=EDGE_CURVE('E308',#611,#603,#609,.T.);
#613=ORIENTED_EDGE('',*,*,#612,.F.);
#614=DIRECTION('',(0.,0.,-1.));
#615=VECTOR('',#614,1.);
#616=CARTESIAN_POINT('',(-32.,0.,22.));
#617=LINE('',#616,#615);
#618=CARTESIAN_POINT('',(-32.,0.,22.));
#619=VERTEX_POINT('',#618);
#620=EDGE_CURVE('E427',#619,#611,#617,.T.);
#621=ORIENTED_EDGE('',*,*,#620,.F.);
#622=DIRECTION('',(0.,-1.,0.));
#623=VECTOR('',#622,1.);
#624=CARTESIAN_POINT('',(-32.,10.,22.));
#625=LINE('',#624,#623);
#626=EDGE_CURVE('E351',#556,#619,#625,.T.);
#627=ORIENTED_EDGE('',*,*,#626,.F.);
#628=EDGE_LOOP('',(#589,#597,#605,#613,#621,#627));
#629=FACE_BOUND('',#628,.T.);
#630=ADVANCED_FACE('F449',(#629),#588,.F.);
#631=CARTESIAN_POINT('',(-32.,0.,22.));
#632=DIRECTION('',(0.,1.,0.));
#633=DIRECTION('',(0.,0.,1.));
#634=AXIS2_PLACEMENT_3D('',#631,#632,#633);
#635=PLANE('',#634);
#636=ORIENTED_EDGE('',*,*,#620,.T.);
#637=DIRECTION('',(-1.,0.,0.));
#638=VECTOR('',#637,1.);
#639=CARTESIAN_POINT('',(-32.,0.,-10.));
#640=LINE('',#639,#638);
#641=EDGE_CURVE('E305',#71,#611,#640,.T.);
#642=ORIENTED_EDGE('',*,*,#641,.F.);
#643=ORIENTED_EDGE('',*,*,#72,.F.);
#644=DIRECTION('',(1.,0.,0.));
#645=VECTOR('',#644,1.);
#646=CARTESIAN_POINT('',(-32.,0.,22.));
#647=LINE('',#646,#645);
#648=EDGE_CURVE('E353',#619,#69,#647,.T.);
#649=ORIENTED_EDGE('',*,*,#648,.F.);
#650=EDGE_LOOP('',(#636,#642,#643,#649));
#651=FACE_BOUND('',#650,.T.);
#652=ADVANCED_FACE('F446',(#651),#635,.F.);
#653=CARTESIAN_POINT('',(0.,20.,22.));
#654=DIRECTION('',(0.,0.,1.));
#655=DIRECTION('',(1.,0.,0.));
#656=AXIS2_PLACEMENT_3D('',#653,#654,#655);
#657=PLANE('',#656);
#658=DIRECTION('',(-1.,0.,0.));
#659=VECTOR('',#658,1.);
#660=CARTESIAN_POINT('',(3.99999999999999,-2.,22.));
#661=LINE('',#660,#659);
#662=CARTESIAN_POINT('',(3.99999999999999,-2.,22.));
#663=VERTEX_POINT('',#662);
#664=EDGE_CURVE('E206',#29,#663,#661,.T.);
#665=ORIENTED_EDGE('',*,*,#664,.F.);
#666=ORIENTED_EDGE('',*,*,#32,.T.);
#667=ORIENTED_EDGE('',*,*,#196,.T.);
#668=ORIENTED_EDGE('',*,*,#243,.T.);
#669=ORIENTED_EDGE('',*,*,#273,.T.);
#670=CARTESIAN_POINT('',(24.2283340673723,13.,22.));
#671=DIRECTION('',(0.,0.,1.));
#672=DIRECTION('',(1.,0.,0.));
#673=AXIS2_PLACEMENT_3D('',#670,#671,#672);
#674=CIRCLE('',#673,3.);
#675=EDGE_CURVE('E48',#266,#289,#674,.F.);
#676=ORIENTED_EDGE('',*,*,#675,.T.);
#677=ORIENTED_EDGE('',*,*,#292,.T.);
#678=ORIENTED_EDGE('',*,*,#507,.T.);
#679=ORIENTED_EDGE('',*,*,#538,.T.);
#680=CARTESIAN_POINT('',(-24.2283340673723,13.,22.));
#681=DIRECTION('',(0.,0.,1.));
#682=DIRECTION('',(1.,0.,0.));
#683=AXIS2_PLACEMENT_3D('',#680,#681,#682);
#684=CIRCLE('',#683,3.);
#685=EDGE_CURVE('E388',#531,#554,#684,.F.);
#686=ORIENTED_EDGE('',*,*,#685,.T.);
#687=ORIENTED_EDGE('',*,*,#557,.T.);
#688=ORIENTED_EDGE('',*,*,#626,.T.);
#689=ORIENTED_EDGE('',*,*,#648,.T.);
#690=ORIENTED_EDGE('',*,*,#94,.T.);
#691=ORIENTED_EDGE('',*,*,#147,.T.);
#692=ORIENTED_EDGE('',*,*,#164,.T.);
#693=DIRECTION('',(1.,0.,0.));
#694=VECTOR('',#693,1.);
#695=CARTESIAN_POINT('',(3.99999999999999,-7.,22.));
#696=LINE('',#695,#694);
#697=CARTESIAN_POINT('',(3.99999999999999,-7.,22.));
#698=VERTEX_POINT('',#697);
#699=EDGE_CURVE('E209',#698,#161,#696,.T.);
#700=ORIENTED_EDGE('',*,*,#699,.F.);
#701=DIRECTION('',(0.,-1.,0.));
#702=VECTOR('',#701,1.);
#703=CARTESIAN_POINT('',(3.99999999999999,-2.,22.));
#704=LINE('',#703,#702);
#705=EDGE_CURVE('E195',#663,#698,#704,.T.);
#706=ORIENTED_EDGE('',*,*,#705,.F.);
#707=EDGE_LOOP('',(#665,#666,#667,#668,#669,#676,#677,#678,#679,#686,#687,#688,#689,#690,#691,
#692,#700,#706));
#708=FACE_BOUND('',#707,.T.);
#709=CARTESIAN_POINT('',(0.,20.,22.));
#710=DIRECTION('',(0.,0.,1.));
#711=DIRECTION('',(1.,0.,0.));
#712=AXIS2_PLACEMENT_3D('',#709,#710,#711);
#713=CIRCLE('',#712,6.);
#714=CARTESIAN_POINT('',(6.,20.,22.));
#715=VERTEX_POINT('',#714);
#716=EDGE_CURVE('E548',#715,#715,#713,.T.);
#717=ORIENTED_EDGE('',*,*,#716,.F.);
#718=EDGE_LOOP('',(#717));
#719=FACE_BOUND('',#718,.T.);
#720=ADVANCED_FACE('F393',(#708,#719),#657,.T.);
#721=CARTESIAN_POINT('',(32.,0.,0.));
#722=DIRECTION('',(0.,0.,1.));
#723=DIRECTION('',(1.,0.,0.));
#724=AXIS2_PLACEMENT_3D('',#721,#722,#723);
#725=PLANE('',#724);
#726=ORIENTED_EDGE('',*,*,#573,.F.);
#727=CARTESIAN_POINT('',(-24.2283340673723,13.,0.));
#728=DIRECTION('',(0.,0.,1.));
#729=DIRECTION('',(1.,0.,0.));
#730=AXIS2_PLACEMENT_3D('',#727,#728,#729);
#731=CIRCLE('',#730,3.);
#732=EDGE_CURVE('E377',#564,#523,#731,.T.);
#733=ORIENTED_EDGE('',*,*,#732,.T.);
#734=ORIENTED_EDGE('',*,*,#524,.F.);
#735=ORIENTED_EDGE('',*,*,#492,.F.);
#736=DIRECTION('',(1.,0.,0.));
#737=VECTOR('',#736,1.);
#738=CARTESIAN_POINT('',(32.,36.,0.));
#739=LINE('',#738,#737);
#740=EDGE_CURVE('E318',#595,#487,#739,.T.);
#741=ORIENTED_EDGE('',*,*,#740,.F.);
#742=ORIENTED_EDGE('',*,*,#596,.F.);
#743=EDGE_LOOP('',(#726,#733,#734,#735,#741,#742));
#744=FACE_BOUND('',#743,.T.);
#745=ADVANCED_FACE('F474',(#744),#725,.T.);
#746=ORIENTED_EDGE('',*,*,#308,.F.);
#747=CARTESIAN_POINT('',(24.2283340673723,13.,0.));
#748=DIRECTION('',(0.,0.,1.));
#749=DIRECTION('',(1.,0.,0.));
#750=AXIS2_PLACEMENT_3D('',#747,#748,#749);
#751=CIRCLE('',#750,3.);
#752=EDGE_CURVE('E385',#299,#258,#751,.T.);
#753=ORIENTED_EDGE('',*,*,#752,.T.);
#754=ORIENTED_EDGE('',*,*,#259,.F.);
#755=ORIENTED_EDGE('',*,*,#229,.F.);
#756=EDGE_CURVE('E324',#487,#220,#739,.T.);
#757=ORIENTED_EDGE('',*,*,#756,.F.);
#758=ORIENTED_EDGE('',*,*,#488,.F.);
#759=EDGE_LOOP('',(#746,#753,#754,#755,#757,#758));
#760=FACE_BOUND('',#759,.T.);
#761=ADVANCED_FACE('F405',(#760),#725,.T.);
#762=CARTESIAN_POINT('',(32.,36.,-10.));
#763=DIRECTION('',(0.,-1.,0.));
#764=DIRECTION('',(0.,0.,-1.));
#765=AXIS2_PLACEMENT_3D('',#762,#763,#764);
#766=PLANE('',#765);
#767=ORIENTED_EDGE('',*,*,#740,.T.);
#768=ORIENTED_EDGE('',*,*,#756,.T.);
#769=ORIENTED_EDGE('',*,*,#221,.F.);
#770=DIRECTION('',(1.,0.,0.));
#771=VECTOR('',#770,1.);
#772=CARTESIAN_POINT('',(32.,36.,-10.));
#773=LINE('',#772,#771);
#774=EDGE_CURVE('E310',#603,#212,#773,.T.);
#775=ORIENTED_EDGE('',*,*,#774,.F.);
#776=ORIENTED_EDGE('',*,*,#604,.T.);
#777=EDGE_LOOP('',(#767,#768,#769,#775,#776));
#778=FACE_BOUND('',#777,.T.);
#779=ADVANCED_FACE('F456',(#778),#766,.F.);
#780=CARTESIAN_POINT('',(32.,0.,-10.));
#781=DIRECTION('',(0.,0.,1.));
#782=DIRECTION('',(1.,0.,0.));
#783=AXIS2_PLACEMENT_3D('',#780,#781,#782);
#784=PLANE('',#783);
#785=ORIENTED_EDGE('',*,*,#48,.T.);
#786=DIRECTION('',(-1.,0.,0.));
#787=VECTOR('',#786,1.);
#788=CARTESIAN_POINT('',(3.99999999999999,-2.,-10.));
#789=LINE('',#788,#787);
#790=CARTESIAN_POINT('',(3.99999999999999,-2.,-10.));
#791=VERTEX_POINT('',#790);
#792=EDGE_CURVE('E197',#39,#791,#789,.T.);
#793=ORIENTED_EDGE('',*,*,#792,.T.);
#794=DIRECTION('',(0.,-1.,0.));
#795=VECTOR('',#794,1.);
#796=CARTESIAN_POINT('',(3.99999999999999,-2.,-10.));
#797=LINE('',#796,#795);
#798=CARTESIAN_POINT('',(3.99999999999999,-7.,-10.));
#799=VERTEX_POINT('',#798);
#800=EDGE_CURVE('E192',#791,#799,#797,.T.);
#801=ORIENTED_EDGE('',*,*,#800,.T.);
#802=DIRECTION('',(1.,0.,0.));
#803=VECTOR('',#802,1.);
#804=CARTESIAN_POINT('',(3.99999999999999,-7.,-10.));
#805=LINE('',#804,#803);
#806=EDGE_CURVE('E199',#799,#153,#805,.T.);
#807=ORIENTED_EDGE('',*,*,#806,.T.);
#808=ORIENTED_EDGE('',*,*,#154,.T.);
#809=ORIENTED_EDGE('',*,*,#133,.T.);
#810=ORIENTED_EDGE('',*,*,#80,.T.);
#811=ORIENTED_EDGE('',*,*,#641,.T.);
#812=ORIENTED_EDGE('',*,*,#612,.T.);
#813=ORIENTED_EDGE('',*,*,#774,.T.);
#814=ORIENTED_EDGE('',*,*,#213,.T.);
#815=ORIENTED_EDGE('',*,*,#182,.T.);
#816=EDGE_LOOP('',(#785,#793,#801,#807,#808,#809,#810,#811,#812,#813,#814,#815));
#817=FACE_BOUND('',#816,.T.);
#818=ADVANCED_FACE('F205',(#817),#784,.F.);
#819=CARTESIAN_POINT('',(-24.2283340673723,13.,22.));
#820=DIRECTION('',(0.,0.,1.));
#821=DIRECTION('',(1.,0.,0.));
#822=AXIS2_PLACEMENT_3D('',#819,#820,#821);
#823=CYLINDRICAL_SURFACE('',#822,3.);
#824=ORIENTED_EDGE('',*,*,#685,.F.);
#825=ORIENTED_EDGE('',*,*,#532,.F.);
#826=ORIENTED_EDGE('',*,*,#732,.F.);
#827=ORIENTED_EDGE('',*,*,#565,.F.);
#828=EDGE_LOOP('',(#824,#825,#826,#827));
#829=FACE_BOUND('',#828,.T.);
#830=ADVANCED_FACE('F510',(#829),#823,.F.);
#831=CARTESIAN_POINT('',(24.2283340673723,13.,22.));
#832=DIRECTION('',(0.,0.,1.));
#833=DIRECTION('',(1.,0.,0.));
#834=AXIS2_PLACEMENT_3D('',#831,#832,#833);
#835=CYLINDRICAL_SURFACE('',#834,3.);
#836=ORIENTED_EDGE('',*,*,#675,.F.);
#837=ORIENTED_EDGE('',*,*,#267,.F.);
#838=ORIENTED_EDGE('',*,*,#752,.F.);
#839=ORIENTED_EDGE('',*,*,#300,.F.);
#840=EDGE_LOOP('',(#836,#837,#838,#839));
#841=FACE_BOUND('',#840,.T.);
#842=ADVANCED_FACE('F38',(#841),#835,.F.);
#843=CARTESIAN_POINT('',(0.,20.,-2.));
#844=DIRECTION('',(0.,0.,1.));
#845=DIRECTION('',(1.,0.,0.));
#846=AXIS2_PLACEMENT_3D('',#843,#844,#845);
#847=CYLINDRICAL_SURFACE('',#846,6.);
#848=CARTESIAN_POINT('',(0.,26.,13.));
#849=CARTESIAN_POINT('',(0.0788941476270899,25.9999993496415,12.9999991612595));
#850=CARTESIAN_POINT('',(0.15779662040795,25.9984386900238,12.9968820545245));
#851=CARTESIAN_POINT('',(0.315001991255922,25.9922435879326,12.98446072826));
#852=CARTESIAN_POINT('',(0.393304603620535,25.987607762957,12.9751537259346));
#853=CARTESIAN_POINT('',(0.626628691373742,25.9692197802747,12.9380421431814));
#854=CARTESIAN_POINT('',(0.779952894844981,25.950987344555,12.9010471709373));
#855=CARTESIAN_POINT('',(1.07683586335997,25.9044896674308,12.8044182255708));
#856=CARTESIAN_POINT('',(1.22043005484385,25.8762634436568,12.7448722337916));
#857=CARTESIAN_POINT('',(1.49540820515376,25.8123730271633,12.6052887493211));
#858=CARTESIAN_POINT('',(1.62679312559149,25.7767094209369,12.5252528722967));
#859=CARTESIAN_POINT('',(1.88252701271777,25.6986875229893,12.3414460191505));
#860=CARTESIAN_POINT('',(2.0059694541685,25.6560547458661,12.2365320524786));
#861=CARTESIAN_POINT('',(2.23433451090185,25.5698003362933,12.0084440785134));
#862=CARTESIAN_POINT('',(2.33924301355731,25.5261779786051,11.8852562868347));
#863=CARTESIAN_POINT('',(2.53576864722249,25.4389634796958,11.6125156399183));
#864=CARTESIAN_POINT('',(2.62572411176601,25.3956360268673,11.4616590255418));
#865=CARTESIAN_POINT('',(2.7403403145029,25.3378244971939,11.2240491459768));
#866=CARTESIAN_POINT('',(2.77516786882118,25.3197457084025,11.1429290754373));
#867=CARTESIAN_POINT('',(2.83769299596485,25.2866576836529,10.9773994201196));
#868=CARTESIAN_POINT('',(2.86539478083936,25.2716466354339,10.8929918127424));
#869=CARTESIAN_POINT('',(2.91188280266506,25.2461034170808,10.7266042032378));
#870=CARTESIAN_POINT('',(2.93110042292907,25.235358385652,10.6447772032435));
#871=CARTESIAN_POINT('',(2.9626355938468,25.2175778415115,10.4794450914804));
#872=CARTESIAN_POINT('',(2.9749568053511,25.2105403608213,10.3959408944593));
#873=CARTESIAN_POINT('',(2.99251382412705,25.2004775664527,10.2279936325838));
#874=CARTESIAN_POINT('',(2.99775389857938,25.1974498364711,10.1435511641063));
#875=CARTESIAN_POINT('',(3.00108452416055,25.1955255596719,9.97450634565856));
#876=CARTESIAN_POINT('',(2.99917575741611,25.1966286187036,9.88990401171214));
#877=CARTESIAN_POINT('',(2.98404973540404,25.2053466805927,9.65724610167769));
#878=CARTESIAN_POINT('',(2.96335042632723,25.2172679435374,9.50975584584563));
#879=CARTESIAN_POINT('',(2.90082280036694,25.2522818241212,9.22080632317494));
#880=CARTESIAN_POINT('',(2.85898775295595,25.2753780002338,9.07934899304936));
#881=CARTESIAN_POINT('',(2.75462843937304,25.3306256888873,8.80232034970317));
#882=CARTESIAN_POINT('',(2.69164495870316,25.36297559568,8.66696288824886));
#883=CARTESIAN_POINT('',(2.54712530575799,25.4331017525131,8.40809503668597));
#884=CARTESIAN_POINT('',(2.46558080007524,25.4708804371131,8.28459000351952));
#885=CARTESIAN_POINT('',(2.27419808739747,25.5533948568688,8.03643690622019));
#886=CARTESIAN_POINT('',(2.16208335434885,25.5984053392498,7.9136295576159));
#887=CARTESIAN_POINT('',(1.91866675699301,25.6864286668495,7.68779356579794));
#888=CARTESIAN_POINT('',(1.78735577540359,25.7294405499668,7.58477437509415));
#889=CARTESIAN_POINT('',(1.50154951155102,25.8110596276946,7.39694306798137));
#890=CARTESIAN_POINT('',(1.3462607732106,25.8493695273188,7.31319859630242));
#891=CARTESIAN_POINT('',(1.02139864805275,25.9147364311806,7.17370889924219));
#892=CARTESIAN_POINT('',(0.851836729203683,25.9418023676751,7.11794144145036));
#893=CARTESIAN_POINT('',(0.518299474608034,25.9797300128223,7.04057379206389));
#894=CARTESIAN_POINT('',(0.355024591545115,25.9917481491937,7.01652629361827));
#895=CARTESIAN_POINT('',(0.0263387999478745,26.0021904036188,6.99560580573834));
#896=CARTESIAN_POINT('',(-0.139071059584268,26.0006209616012,6.99871994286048));
#897=CARTESIAN_POINT('',(-0.453698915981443,25.9847357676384,7.03062006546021));
#898=CARTESIAN_POINT('',(-0.603178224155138,25.9714173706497,7.05739759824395));
#899=CARTESIAN_POINT('',(-0.895220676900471,25.9346651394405,7.1327142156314));
#900=CARTESIAN_POINT('',(-1.03778305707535,25.911230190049,7.18125569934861));
#901=CARTESIAN_POINT('',(-1.31666582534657,25.8555275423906,7.29999539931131));
#902=CARTESIAN_POINT('',(-1.45269119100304,25.8230264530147,7.37077315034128));
#903=CARTESIAN_POINT('',(-1.71138408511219,25.7523192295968,7.53132260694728));
#904=CARTESIAN_POINT('',(-1.83404588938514,25.7141106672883,7.62110240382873));
#905=CARTESIAN_POINT('',(-2.07530306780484,25.6312466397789,7.82728127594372));
#906=CARTESIAN_POINT('',(-2.19231623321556,25.5863265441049,7.94542860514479));
#907=CARTESIAN_POINT('',(-2.40556896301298,25.497871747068,8.1997754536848));
#908=CARTESIAN_POINT('',(-2.50179415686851,25.4543380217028,8.33598735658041));
#909=CARTESIAN_POINT('',(-2.675123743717,25.3715357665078,8.63093096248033));
#910=CARTESIAN_POINT('',(-2.75107648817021,25.3325758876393,8.79043379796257));
#911=CARTESIAN_POINT('',(-2.87424847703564,25.2672221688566,9.12253020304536));
#912=CARTESIAN_POINT('',(-2.92150474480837,25.2408121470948,9.2951065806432));
#913=CARTESIAN_POINT('',(-2.98158506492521,25.2068450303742,9.63073066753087));
#914=CARTESIAN_POINT('',(-2.997278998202,25.1977215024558,9.79310275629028));
#915=CARTESIAN_POINT('',(-3.00206745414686,25.1949606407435,10.1183412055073));
#916=CARTESIAN_POINT('',(-2.99117350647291,25.2013165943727,10.2812073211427));
#917=CARTESIAN_POINT('',(-2.94577840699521,25.227135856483,10.5864504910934));
#918=CARTESIAN_POINT('',(-2.91362505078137,25.2452928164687,10.7293013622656));
#919=CARTESIAN_POINT('',(-2.82952596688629,25.2911305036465,11.0074244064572));
#920=CARTESIAN_POINT('',(-2.77757387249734,25.3188142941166,11.142694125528));
#921=CARTESIAN_POINT('',(-2.65144766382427,25.3828558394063,11.4118743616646));
#922=CARTESIAN_POINT('',(-2.57601505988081,25.4196713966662,11.5450829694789));
#923=CARTESIAN_POINT('',(-2.40645126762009,25.4970602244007,11.7978243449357));
#924=CARTESIAN_POINT('',(-2.31231035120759,25.5376354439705,11.9173499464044));
#925=CARTESIAN_POINT('',(-2.094616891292,25.6238685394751,12.1544228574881));
#926=CARTESIAN_POINT('',(-1.96888052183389,25.6695449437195,12.2699651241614));
#927=CARTESIAN_POINT('',(-1.69843715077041,25.7563371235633,12.478801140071));
#928=CARTESIAN_POINT('',(-1.55371998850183,25.7974504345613,12.5720828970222));
#929=CARTESIAN_POINT('',(-1.32452333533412,25.8525140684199,12.6931781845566));
#930=CARTESIAN_POINT('',(-1.24575314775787,25.8698252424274,12.7305202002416));
#931=CARTESIAN_POINT('',(-1.08479725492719,25.9016884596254,12.7983616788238));
#932=CARTESIAN_POINT('',(-1.00261324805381,25.9162418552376,12.8288644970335));
#933=CARTESIAN_POINT('',(-0.835616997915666,25.9421269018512,12.8826072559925));
#934=CARTESIAN_POINT('',(-0.750810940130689,25.9534655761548,12.905863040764));
#935=CARTESIAN_POINT('',(-0.579142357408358,25.9726077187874,12.9448825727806));
#936=CARTESIAN_POINT('',(-0.492281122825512,25.9804133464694,12.9606508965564));
#937=CARTESIAN_POINT('',(-0.337824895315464,25.9908582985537,12.9816846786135));
#938=CARTESIAN_POINT('',(-0.270495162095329,25.9942803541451,12.988546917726));
#939=CARTESIAN_POINT('',(-0.13544567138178,25.9988515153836,12.9977050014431));
#940=CARTESIAN_POINT('',(-0.067725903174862,26.0000005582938,13.0000007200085));
#941=CARTESIAN_POINT('',(0.,26.,13.));
#942=B_SPLINE_CURVE_WITH_KNOTS('',3,(#848,#849,#850,#851,#852,#853,#854,#855,#856,#857,#858,
#859,#860,#861,#862,#863,#864,#865,#866,#867,#868,#869,#870,#871,#872,#873,#874,#875,#876,#877,
#878,#879,#880,#881,#882,#883,#884,#885,#886,#887,#888,#889,#890,#891,#892,#893,#894,#895,#896,
#897,#898,#899,#900,#901,#902,#903,#904,#905,#906,#907,#908,#909,#910,#911,#912,#913,#914,#915,
#916,#917,#918,#919,#920,#921,#922,#923,#924,#925,#926,#927,#928,#929,#930,#931,#932,#933,#934,
#935,#936,#937,#938,#939,#940,#941),.UNSPECIFIED.,.T.,.F.,(4,2,2,2,2,2,2,2,2,2,2,2,2,2,2,2,2,2,
2,2,2,2,2,2,2,2,2,2,2,2,2,2,2,2,2,2,2,2,2,2,2,2,2,2,2,2,4),(0.,0.236611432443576,
0.473329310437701,0.947100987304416,1.41904300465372,1.89094781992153,2.39140181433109,
2.89223525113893,3.4319083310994,3.70192714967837,3.97178599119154,4.2256372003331,
4.47935352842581,4.73291689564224,4.98645606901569,5.43238672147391,5.87845946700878,
6.33492255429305,6.79159098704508,7.30616358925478,7.82098138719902,8.35970601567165,
8.89800185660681,9.3917140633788,9.88519228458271,10.3404225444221,10.7957029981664,
11.2640010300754,11.7324988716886,12.2470036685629,12.7618630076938,13.3016558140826,
13.8407507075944,14.3280945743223,14.8152271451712,15.2559532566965,15.6968212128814,
16.1673090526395,16.6380421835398,17.1659726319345,17.6941868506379,17.9605054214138,
18.2266930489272,18.4922945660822,18.7577335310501,18.9608446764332,19.1639614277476),.UNSPECIFIED.);
#943=CARTESIAN_POINT('',(0.,26.,13.));
#944=VERTEX_POINT('',#943);
#945=EDGE_CURVE('E226',#944,#944,#942,.T.);
#946=ORIENTED_EDGE('',*,*,#945,.T.);
#947=EDGE_LOOP('',(#946));
#948=FACE_BOUND('',#947,.T.);
#949=CARTESIAN_POINT('',(0.,20.,-2.));
#950=DIRECTION('',(0.,0.,1.));
#951=DIRECTION('',(1.,0.,0.));
#952=AXIS2_PLACEMENT_3D('',#949,#950,#951);
#953=CIRCLE('',#952,6.);
#954=CARTESIAN_POINT('',(6.,20.,-2.));
#955=VERTEX_POINT('',#954);
#956=EDGE_CURVE('E325',#955,#955,#953,.T.);
#957=ORIENTED_EDGE('',*,*,#956,.F.);
#958=EDGE_LOOP('',(#957));
#959=FACE_BOUND('',#958,.T.);
#960=ORIENTED_EDGE('',*,*,#716,.T.);
#961=EDGE_LOOP('',(#960));
#962=FACE_BOUND('',#961,.T.);
#963=ADVANCED_FACE('F511',(#948,#959,#962),#847,.F.);
#964=CARTESIAN_POINT('',(0.,20.,-2.));
#965=DIRECTION('',(0.,0.,1.));
#966=DIRECTION('',(1.,0.,0.));
#967=AXIS2_PLACEMENT_3D('',#964,#965,#966);
#968=PLANE('',#967);
#969=ORIENTED_EDGE('',*,*,#956,.T.);
#970=EDGE_LOOP('',(#969));
#971=FACE_BOUND('',#970,.T.);
#972=ADVANCED_FACE('F514',(#971),#968,.T.);
#973=CARTESIAN_POINT('',(0.,8.,-2.));
#974=DIRECTION('',(0.,-1.,0.));
#975=DIRECTION('',(0.,0.,-1.));
#976=AXIS2_PLACEMENT_3D('',#973,#974,#975);
#977=CONICAL_SURFACE('',#976,3.,1.02974425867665);
#978=CARTESIAN_POINT('',(0.,9.80258185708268,-2.));
#979=VERTEX_POINT('',#978);
#980=VERTEX_LOOP('',#979);
#981=FACE_BOUND('',#980,.T.);
#982=CARTESIAN_POINT('',(0.,8.,-2.));
#983=DIRECTION('',(0.,-1.,0.));
#984=DIRECTION('',(0.,0.,-1.));
#985=AXIS2_PLACEMENT_3D('',#982,#983,#984);
#986=CIRCLE('',#985,3.);
#987=CARTESIAN_POINT('',(0.,8.,-5.));
#988=VERTEX_POINT('',#987);
#989=EDGE_CURVE('E543',#988,#988,#986,.T.);
#990=ORIENTED_EDGE('',*,*,#989,.T.);
#991=EDGE_LOOP('',(#990));
#992=FACE_BOUND('',#991,.T.);
#993=ADVANCED_FACE('F518',(#981,#992),#977,.F.);
#994=CARTESIAN_POINT('',(0.,-9.,-2.));
#995=DIRECTION('',(0.,-1.,0.));
#996=DIRECTION('',(0.,0.,-1.));
#997=AXIS2_PLACEMENT_3D('',#994,#995,#996);
#998=CYLINDRICAL_SURFACE('',#997,3.);
#999=ORIENTED_EDGE('',*,*,#989,.F.);
#1000=EDGE_LOOP('',(#999));
#1001=FACE_BOUND('',#1000,.T.);
#1002=ORIENTED_EDGE('',*,*,#122,.T.);
#1003=EDGE_LOOP('',(#1002));
#1004=FACE_BOUND('',#1003,.T.);
#1005=ADVANCED_FACE('F522',(#1001,#1004),#998,.F.);
#1006=CARTESIAN_POINT('',(0.,8.,14.));
#1007=DIRECTION('',(0.,-1.,0.));
#1008=DIRECTION('',(0.,0.,-1.));
#1009=AXIS2_PLACEMENT_3D('',#1006,#1007,#1008);
#1010=CONICAL_SURFACE('',#1009,3.,1.02974425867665);
#1011=CARTESIAN_POINT('',(0.,9.80258185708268,14.));
#1012=VERTEX_POINT('',#1011);
#1013=VERTEX_LOOP('',#1012);
#1014=FACE_BOUND('',#1013,.T.);
#1015=CARTESIAN_POINT('',(0.,8.,14.));
#1016=DIRECTION('',(0.,-1.,0.));
#1017=DIRECTION('',(0.,0.,-1.));
#1018=AXIS2_PLACEMENT_3D('',#1015,#1016,#1017);
#1019=CIRCLE('',#1018,3.);
#1020=CARTESIAN_POINT('',(0.,8.,11.));
#1021=VERTEX_POINT('',#1020);
#1022=EDGE_CURVE('E537',#1021,#1021,#1019,.T.);
#1023=ORIENTED_EDGE('',*,*,#1022,.T.);
#1024=EDGE_LOOP('',(#1023));
#1025=FACE_BOUND('',#1024,.T.);
#1026=ADVANCED_FACE('F526',(#1014,#1025),#1010,.F.);
#1027=CARTESIAN_POINT('',(0.,-9.,14.));
#1028=DIRECTION('',(0.,-1.,0.));
#1029=DIRECTION('',(0.,0.,-1.));
#1030=AXIS2_PLACEMENT_3D('',#1027,#1028,#1029);
#1031=CYLINDRICAL_SURFACE('',#1030,3.);
#1032=ORIENTED_EDGE('',*,*,#1022,.F.);
#1033=EDGE_LOOP('',(#1032));
#1034=FACE_BOUND('',#1033,.T.);
#1035=ORIENTED_EDGE('',*,*,#111,.T.);
#1036=EDGE_LOOP('',(#1035));
#1037=FACE_BOUND('',#1036,.T.);
#1038=ADVANCED_FACE('F249',(#1034,#1037),#1031,.F.);
#1039=CARTESIAN_POINT('',(0.,36.,10.));
#1040=DIRECTION('',(0.,1.,0.));
#1041=DIRECTION('',(0.,0.,1.));
#1042=AXIS2_PLACEMENT_3D('',#1039,#1040,#1041);
#1043=CYLINDRICAL_SURFACE('',#1042,6.);
#1044=CARTESIAN_POINT('',(0.,32.,10.));
#1045=DIRECTION('',(0.,1.,0.));
#1046=DIRECTION('',(0.,0.,1.));
#1047=AXIS2_PLACEMENT_3D('',#1044,#1045,#1046);
#1048=CIRCLE('',#1047,6.);
#1049=CARTESIAN_POINT('',(0.,32.,16.));
#1050=VERTEX_POINT('',#1049);
#1051=EDGE_CURVE('E217',#1050,#1050,#1048,.T.);
#1052=ORIENTED_EDGE('',*,*,#1051,.F.);
#1053=EDGE_LOOP('',(#1052));
#1054=FACE_BOUND('',#1053,.T.);
#1055=ORIENTED_EDGE('',*,*,#477,.F.);
#1056=EDGE_LOOP('',(#1055));
#1057=FACE_BOUND('',#1056,.T.);
#1058=ADVANCED_FACE('F242',(#1054,#1057),#1043,.F.);
#1059=CARTESIAN_POINT('',(0.,36.,10.));
#1060=DIRECTION('',(0.,1.,0.));
#1061=DIRECTION('',(0.,0.,1.));
#1062=AXIS2_PLACEMENT_3D('',#1059,#1060,#1061);
#1063=CYLINDRICAL_SURFACE('',#1062,3.);
#1064=ORIENTED_EDGE('',*,*,#945,.F.);
#1065=EDGE_LOOP('',(#1064));
#1066=FACE_BOUND('',#1065,.T.);
#1067=CARTESIAN_POINT('',(0.,32.,10.));
#1068=DIRECTION('',(0.,1.,0.));
#1069=DIRECTION('',(0.,0.,1.));
#1070=AXIS2_PLACEMENT_3D('',#1067,#1068,#1069);
#1071=CIRCLE('',#1070,3.);
#1072=CARTESIAN_POINT('',(0.,32.,13.));
#1073=VERTEX_POINT('',#1072);
#1074=EDGE_CURVE('E223',#1073,#1073,#1071,.T.);
#1075=ORIENTED_EDGE('',*,*,#1074,.T.);
#1076=EDGE_LOOP('',(#1075));
#1077=FACE_BOUND('',#1076,.T.);
#1078=ADVANCED_FACE('F237',(#1066,#1077),#1063,.F.);
#1079=CARTESIAN_POINT('',(3.,32.,10.));
#1080=DIRECTION('',(0.,-1.,0.));
#1081=DIRECTION('',(0.,0.,-1.));
#1082=AXIS2_PLACEMENT_3D('',#1079,#1080,#1081);
#1083=PLANE('',#1082);
#1084=ORIENTED_EDGE('',*,*,#1074,.F.);
#1085=EDGE_LOOP('',(#1084));
#1086=FACE_BOUND('',#1085,.T.);
#1087=ORIENTED_EDGE('',*,*,#1051,.T.);
#1088=EDGE_LOOP('',(#1087));
#1089=FACE_BOUND('',#1088,.T.);
#1090=ADVANCED_FACE('F241',(#1086,#1089),#1083,.F.);
#1091=CARTESIAN_POINT('',(3.99999999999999,-2.,-10.));
#1092=DIRECTION('',(-1.,0.,0.));
#1093=DIRECTION('',(0.,-1.,0.));
#1094=AXIS2_PLACEMENT_3D('',#1091,#1092,#1093);
#1095=PLANE('',#1094);
#1096=ORIENTED_EDGE('',*,*,#705,.T.);
#1097=DIRECTION('',(0.,0.,1.));
#1098=VECTOR('',#1097,1.);
#1099=CARTESIAN_POINT('',(3.99999999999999,-7.,-10.));
#1100=LINE('',#1099,#1098);
#1101=EDGE_CURVE('E189',#799,#698,#1100,.T.);
#1102=ORIENTED_EDGE('',*,*,#1101,.F.);
#1103=ORIENTED_EDGE('',*,*,#800,.F.);
#1104=DIRECTION('',(0.,0.,1.));
#1105=VECTOR('',#1104,1.);
#1106=CARTESIAN_POINT('',(3.99999999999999,-2.,-10.));
#1107=LINE('',#1106,#1105);
#1108=EDGE_CURVE('E215',#791,#663,#1107,.T.);
#1109=ORIENTED_EDGE('',*,*,#1108,.T.);
#1110=EDGE_LOOP('',(#1096,#1102,#1103,#1109));
#1111=FACE_BOUND('',#1110,.T.);
#1112=ADVANCED_FACE('F190',(#1111),#1095,.F.);
#1113=CARTESIAN_POINT('',(3.99999999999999,-2.,-10.));
#1114=DIRECTION('',(0.,1.,0.));
#1115=DIRECTION('',(0.,0.,1.));
#1116=AXIS2_PLACEMENT_3D('',#1113,#1114,#1115);
#1117=PLANE('',#1116);
#1118=ORIENTED_EDGE('',*,*,#664,.T.);
#1119=ORIENTED_EDGE('',*,*,#1108,.F.);
#1120=ORIENTED_EDGE('',*,*,#792,.F.);
#1121=ORIENTED_EDGE('',*,*,#40,.T.);
#1122=EDGE_LOOP('',(#1118,#1119,#1120,#1121));
#1123=FACE_BOUND('',#1122,.T.);
#1124=ADVANCED_FACE('F253',(#1123),#1117,.F.);
#1125=CARTESIAN_POINT('',(3.99999999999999,-7.,-10.));
#1126=DIRECTION('',(0.,-1.,0.));
#1127=DIRECTION('',(0.,0.,-1.));
#1128=AXIS2_PLACEMENT_3D('',#1125,#1126,#1127);
#1129=PLANE('',#1128);
#1130=ORIENTED_EDGE('',*,*,#699,.T.);
#1131=ORIENTED_EDGE('',*,*,#162,.F.);
#1132=ORIENTED_EDGE('',*,*,#806,.F.);
#1133=ORIENTED_EDGE('',*,*,#1101,.T.);
#1134=EDGE_LOOP('',(#1130,#1131,#1132,#1133));
#1135=FACE_BOUND('',#1134,.T.);
#1136=ADVANCED_FACE('F200',(#1135),#1129,.F.);
#1137=CLOSED_SHELL('',(#58,#98,#151,#169,#200,#247,#278,#318,#512,#543,#583,#630,#652,#720,#745,
#761,#779,#818,#830,#842,#963,#972,#993,#1005,#1026,#1038,#1058,#1078,#1090,#1112,#1124,#1136));
#1138=MANIFOLD_SOLID_BREP('B2',#1137);
#1139=ADVANCED_BREP_SHAPE_REPRESENTATION('',(#18,#1138),#14);
#1140=SHAPE_DEFINITION_REPRESENTATION(#9,#1139);
ENDSEC;
END-ISO-10303-21;
